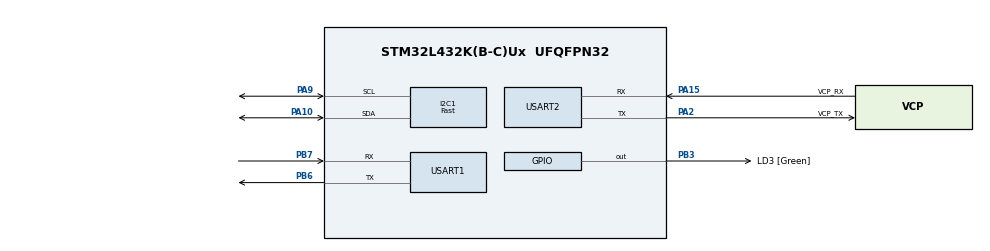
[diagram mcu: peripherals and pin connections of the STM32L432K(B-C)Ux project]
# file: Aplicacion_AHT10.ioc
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I2C1.I2C_Speed_Mode=I2C_Fast
I2C1.Timing=0x0010061A
Mcu.Family=STM32L4
Mcu.Name=STM32L432K(B-C)Ux
Mcu.Package=UFQFPN32
NVIC.PriorityGroup=NVIC_PRIORITYGROUP_4
NVIC.USART1_IRQn=true\:0\:0\:false\:false\:true\:true\:true
NVIC.USART2_IRQn=true\:0\:0\:false\:false\:true\:true\:true
PA0.GPIO_Label=MCO [High speed clock in]
PA0.Signal=RCC_CK_IN
PA10.Mode=I2C
PA10.Signal=I2C1_SDA
PA13\ (JTMS-SWDIO).GPIO_Label=SWDIO
PA13\ (JTMS-SWDIO).Mode=Serial_Wire
PA13\ (JTMS-SWDIO).Signal=SYS_JTMS-SWDIO
PA14\ (JTCK-SWCLK).GPIO_Label=SWCLK
PA14\ (JTCK-SWCLK).Mode=Serial_Wire
PA14\ (JTCK-SWCLK).Signal=SYS_JTCK-SWCLK
PA15\ (JTDI).GPIO_Label=VCP_RX
PA15\ (JTDI).GPIO_Speed=GPIO_SPEED_FREQ_VERY_HIGH
PA15\ (JTDI).Mode=Asynchronous
PA15\ (JTDI).Signal=USART2_RX
PA2.GPIO_Label=VCP_TX
PA2.Mode=Asynchronous
PA2.Signal=USART2_TX
PA9.Mode=I2C
PA9.Signal=I2C1_SCL
PB3\ (JTDO-TRACESWO).GPIO_Label=LD3 [Green]
PB3\ (JTDO-TRACESWO).Signal=GPIO_Output
PB6.Mode=Asynchronous
PB6.Signal=USART1_TX
PB7.Mode=Asynchronous
PB7.Signal=USART1_RX
PC14-OSC32_IN\ (PC14).Signal=RCC_OSC32_IN
PC15-OSC32_OUT\ (PC15).Signal=RCC_OSC32_OUT
ProjectManager.HeapSize=0x200
ProjectManager.StackSize=0x400
ProjectManager.TargetToolchain=STM32CubeIDE
RCC.ADCFreq_Value=16000000
RCC.AHBCLKDivider=RCC_SYSCLK_DIV2
RCC.AHBFreq_Value=16000000
RCC.APB1Freq_Value=16000000
RCC.APB1TimFreq_Value=16000000
RCC.APB2Freq_Value=16000000
RCC.APB2TimFreq_Value=16000000
RCC.CortexFreq_Value=16000000
RCC.HCLKFreq_Value=16000000
RCC.HSE_VALUE=8000000
RCC.HSI16_VALUE=16000000
RCC.HSI48_VALUE=48000000
RCC.HSI_VALUE=16000000
RCC.MSI_VALUE=4000000
RCC.PLLMUL=RCC_PLLMUL_4
RCC.PLLN=40
RCC.SYSCLKFreq_VALUE=16000000
RCC.SYSCLKSource=RCC_SYSCLKSOURCE_HSI
RCC.USART1CLockSelection=RCC_USART1CLKSOURCE_SYSCLK
RCC.USART2CLockSelection=RCC_USART2CLKSOURCE_SYSCLK
RCC.USBFreq_Value=16000000
RCC.VCOOutputFreq_Value=160000000
USART1.VirtualMode-Asynchronous=VM_ASYNC
USART2.VirtualMode-Asynchronous=VM_ASYNC
board=NUCLEO-L432KC

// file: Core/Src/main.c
/* USER CODE BEGIN Header */
/**
  ******************************************************************************
  * @author  Mario Aguilar Montoya
  * @date    10/15/2021
  * @file           : main.c
  * @brief          : Main program body
  ******************************************************************************
  * @attention
  *
  * <h2><center>&copy; Copyright (c) 2021 STMicroelectronics.
  * All rights reserved.</center></h2>
  *
  * This software component is licensed by ST under BSD 3-Clause license,
  * the "License"; You may not use this file except in compliance with the
  * License. You may obtain a copy of the License at:
  *                        opensource.org/licenses/BSD-3-Clause
  *
  ******************************************************************************
  */
/* USER CODE END Header */
#include "main.h"
/* USER CODE BEGIN Includes */
#include "driver_bg96.h"
#include "aht10_STM32L432_port.h"
#include "aht10.h"
#include "MAX17043.h"
/* USER CODE END Includes */

UART_HandleTypeDef huart1;
UART_HandleTypeDef huart2;
aht10_config_t aht10_config;
max17043_data  max17043_config;

void SystemClock_Config(void);
static void MX_GPIO_Init(void);
//MX_USART2_UART_Init(void);
//MX_I2C1_Init(void);
void MX_USART1_UART_Init(void);
em_bg96_error_handling send_data(char*cmd, char*expect,char *buffer,uint32_t timeout);

/* USER CODE BEGIN 0 */

typedef enum
{
	VERIFICARCONEXION,
	SETEAR_APN,
	ACTIVAR_PDP,
	OPEN_SERVER,
	CONECTAR_MQTT,
	PUBLICAR_MQTT,
	DESCONECTAR_MQTT,
	DESCONECTAR_PDP,
}estados_mqtt;
st_bg96_config config_module={.send_data_device=NULL,.mode_echo=STATE_ECHO_OFF,.format_response=SHORT_RESULT};
char buffer[150];
char bufferhuart2[150];
char data2[60]="{\"temperatura\":40,\"humedad\":40,\"bateria\":40}";
uint8_t cont1=2;
uint8_t cont2=5;
uint8_t cont3=8;
uint8_t cont4=0;

/* USER CODE END 0 */

int main(void)
{

  /* MCU Configuration--------------------------------------------------------*/

  /* Reset of all peripherals, Initializes the Flash interface and the Systick. */
  HAL_Init();

  /* Configure the system clock */
  SystemClock_Config();

  /* Initialize all configured peripherals */
  MX_GPIO_Init();
  MX_USART2_UART_Init();
  MX_I2C1_Init();
  MX_USART1_UART_Init();
  aht10Init(&aht10_config,write_I2C_STM32L432_port,read_I2C_STM32L432_port,delay_STM32L432_port);
  init_driver(&config_module,send_data);
  /* Infinite loop */
  /* USER CODE BEGIN WHILE */
  //aht10_start_measurement(&aht10_config);
  int8_t temperatura=0;
  uint8_t humedad=0;
  char buffersensore[50];
  while (1)
  {
	  aht10_launch_measurement(&aht10_config);
	  aht10_get_humedity(&aht10_config, &humedad);
	  aht10_get_temperature(&aht10_config, &temperatura);
	  sprintf(buffersensore,"humedad:%u  temperatura:%i \r\n",humedad,temperatura);
	  HAL_UART_Transmit(&huart2,buffersensore,50,200);
	  HAL_Delay(200);

  }
  /* USER CODE END 3 */
}

void SystemClock_Config(void)
{
  RCC_OscInitTypeDef RCC_OscInitStruct = {0};
  RCC_ClkInitTypeDef RCC_ClkInitStruct = {0};

  /** Configure the main internal regulator output voltage
  */
  if (HAL_PWREx_ControlVoltageScaling(PWR_REGULATOR_VOLTAGE_SCALE1) != HAL_OK)
  {
    Error_Handler();
  }
  /** Initializes the RCC Oscillators according to the specified parameters
  * in the RCC_OscInitTypeDef structure.
  */
  RCC_OscInitStruct.OscillatorType = RCC_OSCILLATORTYPE_HSI;
  RCC_OscInitStruct.HSIState = RCC_HSI_ON;
  RCC_OscInitStruct.HSICalibrationValue = RCC_HSICALIBRATION_DEFAULT;
  RCC_OscInitStruct.PLL.PLLState = RCC_PLL_NONE;
  if (HAL_RCC_OscConfig(&RCC_OscInitStruct) != HAL_OK)
  {
    Error_Handler();
  }
  /** Initializes the CPU, AHB and APB buses clocks
  */
  RCC_ClkInitStruct.ClockType = RCC_CLOCKTYPE_HCLK|RCC_CLOCKTYPE_SYSCLK
                              |RCC_CLOCKTYPE_PCLK1|RCC_CLOCKTYPE_PCLK2;
  RCC_ClkInitStruct.SYSCLKSource = RCC_SYSCLKSOURCE_HSI;
  RCC_ClkInitStruct.AHBCLKDivider = RCC_SYSCLK_DIV2;
  RCC_ClkInitStruct.APB1CLKDivider = RCC_HCLK_DIV1;
  RCC_ClkInitStruct.APB2CLKDivider = RCC_HCLK_DIV1;

  if (HAL_RCC_ClockConfig(&RCC_ClkInitStruct, FLASH_LATENCY_0) != HAL_OK)
  {
    Error_Handler();
  }
}

void MX_USART1_UART_Init(void)
{

    huart1.Instance = USART1;
    huart1.Init.BaudRate = 115200;
    huart1.Init.WordLength = UART_WORDLENGTH_8B;
    huart1.Init.StopBits = UART_STOPBITS_1;
    huart1.Init.Parity = UART_PARITY_NONE;
    huart1.Init.Mode = UART_MODE_TX_RX;
    huart1.Init.HwFlowCtl = UART_HWCONTROL_NONE;
    huart1.Init.OverSampling = UART_OVERSAMPLING_16;
    huart1.Init.OneBitSampling = UART_ONE_BIT_SAMPLE_DISABLE;
    huart1.AdvancedInit.AdvFeatureInit = UART_ADVFEATURE_NO_INIT;
    if (HAL_UART_Init(&huart1) != HAL_OK)
    {
    	Error_Handler();
    }

	}

//void MX_USART2_UART_Init(void)
//{

//  huart2.Instance = USART2;
 // huart2.Init.BaudRate = 115200;
 // huart2.Init.WordLength = UART_WORDLENGTH_8B;
  //huart2.Init.StopBits = UART_STOPBITS_1;
 // huart2.Init.Parity = UART_PARITY_NONE;
 // huart2.Init.Mode = UART_MODE_TX_RX;
 // huart2.Init.HwFlowCtl = UART_HWCONTROL_NONE;
 // huart2.Init.OverSampling = UART_OVERSAMPLING_16;
 // huart2.Init.OneBitSampling = UART_ONE_BIT_SAMPLE_DISABLE;
 // huart2.AdvancedInit.AdvFeatureInit = UART_ADVFEATURE_NO_INIT;
  //if (HAL_UART_Init(&huart2) != HAL_OK)
 // {
  //  Error_Handler();
 // }

//}

static void MX_GPIO_Init(void)
{
  GPIO_InitTypeDef GPIO_InitStruct = {0};

  /* GPIO Ports Clock Enable */
  __HAL_RCC_GPIOC_CLK_ENABLE();
  __HAL_RCC_GPIOA_CLK_ENABLE();
  __HAL_RCC_GPIOB_CLK_ENABLE();

  /*Configure GPIO pin Output Level */
  HAL_GPIO_WritePin(LD3_GPIO_Port, LD3_Pin, GPIO_PIN_RESET);

  /*Configure GPIO pin : LD3_Pin */
  GPIO_InitStruct.Pin = LD3_Pin;
  GPIO_InitStruct.Mode = GPIO_MODE_OUTPUT_PP;
  GPIO_InitStruct.Pull = GPIO_NOPULL;
  GPIO_InitStruct.Speed = GPIO_SPEED_FREQ_LOW;
  HAL_GPIO_Init(LD3_GPIO_Port, &GPIO_InitStruct);

}

/* USER CODE BEGIN 4 */
em_bg96_error_handling send_data(char*cmd, char*expect,char *buffer,uint32_t timeout)
{
	HAL_UART_Transmit(&huart2,cmd,strlen(cmd),300);
	HAL_UART_Transmit(&huart1,cmd,strlen(cmd),300);

	HAL_UART_Receive_IT(&huart1,buffer,150);
	for (uint8_t i= 0; i<timeout; i++)
	{
		HAL_Delay(1);
		if (expect !=NULL)
			{
				if(strstr(buffer,expect)!=NULL)
					{
						HAL_UART_Transmit(&huart2,buffer,strlen(buffer),500);
						HAL_UART_AbortReceive_IT(&huart1);
						return FT_BG96_OK;
					}
			}
	}
	HAL_UART_AbortReceive_IT(&huart1);
	return FT_BG96_TIMEOUT;
}

void HAL_UART_AbortReceiveCpltCallback(UART_HandleTypeDef *huart)
{
	memset(buffer,0,150);
	//HAL_UART_Receive_IT(&huart1,buffer,150);
}

/* USER CODE END 4 */

void Error_Handler(void)
{
  __disable_irq();
  while (1)
  {
  }
}

/************************ (C) COPYRIGHT STMicroelectronics *****END OF FILE****/
